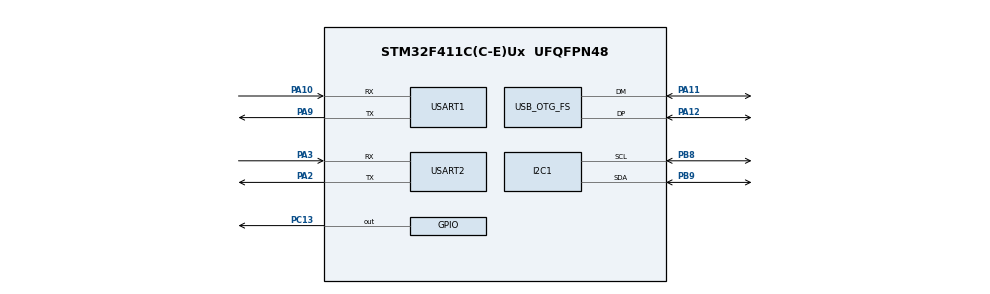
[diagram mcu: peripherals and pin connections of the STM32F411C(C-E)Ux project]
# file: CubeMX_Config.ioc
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ADC1.Channel-0\#ChannelRegularConversion=ADC_CHANNEL_TEMPSENSOR
ADC1.NbrOfConversionFlag=1
ADC1.Rank-0\#ChannelRegularConversion=1
ADC1.SamplingTime-0\#ChannelRegularConversion=ADC_SAMPLETIME_3CYCLES
ADC1.master=1
Mcu.Family=STM32F4
Mcu.Name=STM32F411C(C-E)Ux
Mcu.Package=UFQFPN48
NVIC.PriorityGroup=NVIC_PRIORITYGROUP_4
PA10.GPIO_PuPd=GPIO_PULLUP
PA10.Mode=Asynchronous
PA10.Signal=USART1_RX
PA11.Mode=Device_Only
PA11.Signal=USB_OTG_FS_DM
PA12.Mode=Device_Only
PA12.Signal=USB_OTG_FS_DP
PA13.Mode=Serial_Wire
PA13.Signal=SYS_JTMS-SWDIO
PA14.Mode=Serial_Wire
PA14.Signal=SYS_JTCK-SWCLK
PA2.Mode=Asynchronous
PA2.Signal=USART2_TX
PA3.Mode=Asynchronous
PA3.Signal=USART2_RX
PA9.GPIO_PuPd=GPIO_PULLUP
PA9.Mode=Asynchronous
PA9.Signal=USART1_TX
PB8.Mode=I2C
PB8.Signal=I2C1_SCL
PB9.Mode=I2C
PB9.Signal=I2C1_SDA
PC13-ANTI_TAMP.Signal=GPIO_Output
PC14-OSC32_IN.Mode=LSE-External-Oscillator
PC14-OSC32_IN.Signal=RCC_OSC32_IN
PC15-OSC32_OUT.Mode=LSE-External-Oscillator
PC15-OSC32_OUT.Signal=RCC_OSC32_OUT
PH0\ -\ OSC_IN.Mode=HSE-External-Oscillator
PH0\ -\ OSC_IN.Signal=RCC_OSC_IN
PH1\ -\ OSC_OUT.Mode=HSE-External-Oscillator
PH1\ -\ OSC_OUT.Signal=RCC_OSC_OUT
ProjectManager.HeapSize=0x200
ProjectManager.StackSize=0x400
ProjectManager.TargetToolchain=MDK-ARM V5
RCC.48MHZClocksFreq_Value=48000000
RCC.AHBFreq_Value=96000000
RCC.APB1CLKDivider=RCC_HCLK_DIV2
RCC.APB1Freq_Value=48000000
RCC.APB1TimFreq_Value=96000000
RCC.APB2Freq_Value=96000000
RCC.APB2TimFreq_Value=96000000
RCC.CortexFreq_Value=96000000
RCC.HCLKFreq_Value=96000000
RCC.HSE_VALUE=8000000
RCC.HSI_VALUE=16000000
RCC.PLLM=4
RCC.PLLN=96
RCC.RCC_RTC_Clock_Source=RCC_RTCCLKSOURCE_LSI
RCC.RCC_RTC_Clock_SourceVirtual=RCC_RTCCLKSOURCE_LSE
RCC.SYSCLKFreq_VALUE=96000000
RCC.SYSCLKSource=RCC_SYSCLKSOURCE_PLLCLK
RCC.VCOOutputFreq_Value=192000000
USART1.VirtualMode=VM_ASYNC
USART2.VirtualMode=VM_ASYNC
USB_OTG_FS.VirtualMode=Device_Only
VP_ADC1_TempSens_Input.Mode=IN-TempSens
VP_ADC1_Vref_Input.Mode=IN-Vrefint
VP_RTC_VS_RTC_Activate.Mode=RTC_Enabled
VP_TIM10_VS_ClockSourceINT.Mode=Enable_Timer
VP_TIM11_VS_ClockSourceINT.Mode=Enable_Timer
VP_TIM1_VS_ClockSourceINT.Mode=Internal
VP_TIM4_VS_ClockSourceINT.Mode=Internal
board=custom

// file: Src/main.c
/* USER CODE BEGIN Header */
/**
  ******************************************************************************
  * @file           : main.c
  * @brief          : Main program body
  ******************************************************************************
  * @attention
  *
  * Copyright (c) 2025 STMicroelectronics.
  * All rights reserved.
  *
  * This software is licensed under terms that can be found in the LICENSE file
  * in the root directory of this software component.
  * If no LICENSE file comes with this software, it is provided AS-IS.
  *
  ******************************************************************************
  */
/* USER CODE END Header */
#include "main.h"

 ADC_HandleTypeDef hadc1;

I2C_HandleTypeDef hi2c1;

RTC_HandleTypeDef hrtc;

TIM_HandleTypeDef htim1;
TIM_HandleTypeDef htim4;
TIM_HandleTypeDef htim10;
TIM_HandleTypeDef htim11;

UART_HandleTypeDef huart1;
UART_HandleTypeDef huart2;

PCD_HandleTypeDef hpcd_USB_OTG_FS;

void SystemClock_Config(void);
static void MX_GPIO_Init(void);
static void MX_USART1_UART_Init(void);
static void MX_RTC_Init(void);
static void MX_TIM10_Init(void);
static void MX_TIM11_Init(void);
static void MX_USB_OTG_FS_PCD_Init(void);
static void MX_ADC1_Init(void);
static void MX_TIM1_Init(void);
static void MX_TIM4_Init(void);
static void MX_USART2_UART_Init(void);
static void MX_I2C1_Init(void);

int main(void)
{

  /* MCU Configuration--------------------------------------------------------*/

  /* Reset of all peripherals, Initializes the Flash interface and the Systick. */
  HAL_Init();

  /* Configure the system clock */
  SystemClock_Config();

  /* Initialize all configured peripherals */
  MX_GPIO_Init();
  MX_USART1_UART_Init();
  MX_RTC_Init();
  MX_TIM10_Init();
  MX_TIM11_Init();
  MX_USB_OTG_FS_PCD_Init();
  MX_ADC1_Init();
  MX_TIM1_Init();
  MX_TIM4_Init();
  MX_USART2_UART_Init();
  MX_I2C1_Init();

  /* Infinite loop */
  while (1)
  {

  }
}

void SystemClock_Config(void)
{
  RCC_OscInitTypeDef RCC_OscInitStruct = {0};
  RCC_ClkInitTypeDef RCC_ClkInitStruct = {0};

  /** Configure the main internal regulator output voltage
  */
  __HAL_RCC_PWR_CLK_ENABLE();
  __HAL_PWR_VOLTAGESCALING_CONFIG(PWR_REGULATOR_VOLTAGE_SCALE1);

  /** Initializes the RCC Oscillators according to the specified parameters
  * in the RCC_OscInitTypeDef structure.
  */
  RCC_OscInitStruct.OscillatorType = RCC_OSCILLATORTYPE_HSE|RCC_OSCILLATORTYPE_LSE;
  RCC_OscInitStruct.HSEState = RCC_HSE_ON;
  RCC_OscInitStruct.LSEState = RCC_LSE_ON;
  RCC_OscInitStruct.PLL.PLLState = RCC_PLL_ON;
  RCC_OscInitStruct.PLL.PLLSource = RCC_PLLSOURCE_HSE;
  RCC_OscInitStruct.PLL.PLLM = 15;
  RCC_OscInitStruct.PLL.PLLN = 144;
  RCC_OscInitStruct.PLL.PLLP = RCC_PLLP_DIV4;
  RCC_OscInitStruct.PLL.PLLQ = 5;
  if (HAL_RCC_OscConfig(&RCC_OscInitStruct) != HAL_OK)
  {
    Error_Handler();
  }

  /** Initializes the CPU, AHB and APB buses clocks
  */
  RCC_ClkInitStruct.ClockType = RCC_CLOCKTYPE_HCLK|RCC_CLOCKTYPE_SYSCLK
                              |RCC_CLOCKTYPE_PCLK1|RCC_CLOCKTYPE_PCLK2;
  RCC_ClkInitStruct.SYSCLKSource = RCC_SYSCLKSOURCE_PLLCLK;
  RCC_ClkInitStruct.AHBCLKDivider = RCC_SYSCLK_DIV1;
  RCC_ClkInitStruct.APB1CLKDivider = RCC_HCLK_DIV2;
  RCC_ClkInitStruct.APB2CLKDivider = RCC_HCLK_DIV1;

  if (HAL_RCC_ClockConfig(&RCC_ClkInitStruct, FLASH_LATENCY_1) != HAL_OK)
  {
    Error_Handler();
  }
}

static void MX_ADC1_Init(void)
{

  ADC_ChannelConfTypeDef sConfig = {0};

  /** Configure the global features of the ADC (Clock, Resolution, Data Alignment and number of conversion)
  */
  hadc1.Instance = ADC1;
  hadc1.Init.ClockPrescaler = ADC_CLOCK_SYNC_PCLK_DIV2;
  hadc1.Init.Resolution = ADC_RESOLUTION_12B;
  hadc1.Init.ScanConvMode = DISABLE;
  hadc1.Init.ContinuousConvMode = DISABLE;
  hadc1.Init.DiscontinuousConvMode = DISABLE;
  hadc1.Init.ExternalTrigConvEdge = ADC_EXTERNALTRIGCONVEDGE_NONE;
  hadc1.Init.ExternalTrigConv = ADC_SOFTWARE_START;
  hadc1.Init.DataAlign = ADC_DATAALIGN_RIGHT;
  hadc1.Init.NbrOfConversion = 1;
  hadc1.Init.DMAContinuousRequests = DISABLE;
  hadc1.Init.EOCSelection = ADC_EOC_SINGLE_CONV;
  if (HAL_ADC_Init(&hadc1) != HAL_OK)
  {
    Error_Handler();
  }

  /** Configure for the selected ADC regular channel its corresponding rank in the sequencer and its sample time.
  */
  sConfig.Channel = ADC_CHANNEL_TEMPSENSOR;
  sConfig.Rank = 1;
  sConfig.SamplingTime = ADC_SAMPLETIME_3CYCLES;
  if (HAL_ADC_ConfigChannel(&hadc1, &sConfig) != HAL_OK)
  {
    Error_Handler();
  }

}

static void MX_I2C1_Init(void)
{

  hi2c1.Instance = I2C1;
  hi2c1.Init.ClockSpeed = 100000;
  hi2c1.Init.DutyCycle = I2C_DUTYCYCLE_2;
  hi2c1.Init.OwnAddress1 = 0;
  hi2c1.Init.AddressingMode = I2C_ADDRESSINGMODE_7BIT;
  hi2c1.Init.DualAddressMode = I2C_DUALADDRESS_DISABLE;
  hi2c1.Init.OwnAddress2 = 0;
  hi2c1.Init.GeneralCallMode = I2C_GENERALCALL_DISABLE;
  hi2c1.Init.NoStretchMode = I2C_NOSTRETCH_DISABLE;
  if (HAL_I2C_Init(&hi2c1) != HAL_OK)
  {
    Error_Handler();
  }

}

static void MX_RTC_Init(void)
{

  /** Initialize RTC Only
  */
  hrtc.Instance = RTC;
  hrtc.Init.HourFormat = RTC_HOURFORMAT_24;
  hrtc.Init.AsynchPrediv = 127;
  hrtc.Init.SynchPrediv = 255;
  hrtc.Init.OutPut = RTC_OUTPUT_DISABLE;
  hrtc.Init.OutPutPolarity = RTC_OUTPUT_POLARITY_HIGH;
  hrtc.Init.OutPutType = RTC_OUTPUT_TYPE_OPENDRAIN;
  if (HAL_RTC_Init(&hrtc) != HAL_OK)
  {
    Error_Handler();
  }

}

static void MX_TIM1_Init(void)
{

  TIM_ClockConfigTypeDef sClockSourceConfig = {0};
  TIM_MasterConfigTypeDef sMasterConfig = {0};

  htim1.Instance = TIM1;
  htim1.Init.Prescaler = 0;
  htim1.Init.CounterMode = TIM_COUNTERMODE_UP;
  htim1.Init.Period = 65535;
  htim1.Init.ClockDivision = TIM_CLOCKDIVISION_DIV1;
  htim1.Init.RepetitionCounter = 0;
  htim1.Init.AutoReloadPreload = TIM_AUTORELOAD_PRELOAD_DISABLE;
  if (HAL_TIM_Base_Init(&htim1) != HAL_OK)
  {
    Error_Handler();
  }
  sClockSourceConfig.ClockSource = TIM_CLOCKSOURCE_INTERNAL;
  if (HAL_TIM_ConfigClockSource(&htim1, &sClockSourceConfig) != HAL_OK)
  {
    Error_Handler();
  }
  sMasterConfig.MasterOutputTrigger = TIM_TRGO_RESET;
  sMasterConfig.MasterSlaveMode = TIM_MASTERSLAVEMODE_DISABLE;
  if (HAL_TIMEx_MasterConfigSynchronization(&htim1, &sMasterConfig) != HAL_OK)
  {
    Error_Handler();
  }

}

static void MX_TIM4_Init(void)
{

  TIM_ClockConfigTypeDef sClockSourceConfig = {0};
  TIM_MasterConfigTypeDef sMasterConfig = {0};

  htim4.Instance = TIM4;
  htim4.Init.Prescaler = 0;
  htim4.Init.CounterMode = TIM_COUNTERMODE_UP;
  htim4.Init.Period = 65535;
  htim4.Init.ClockDivision = TIM_CLOCKDIVISION_DIV1;
  htim4.Init.AutoReloadPreload = TIM_AUTORELOAD_PRELOAD_DISABLE;
  if (HAL_TIM_Base_Init(&htim4) != HAL_OK)
  {
    Error_Handler();
  }
  sClockSourceConfig.ClockSource = TIM_CLOCKSOURCE_INTERNAL;
  if (HAL_TIM_ConfigClockSource(&htim4, &sClockSourceConfig) != HAL_OK)
  {
    Error_Handler();
  }
  sMasterConfig.MasterOutputTrigger = TIM_TRGO_RESET;
  sMasterConfig.MasterSlaveMode = TIM_MASTERSLAVEMODE_DISABLE;
  if (HAL_TIMEx_MasterConfigSynchronization(&htim4, &sMasterConfig) != HAL_OK)
  {
    Error_Handler();
  }

}

static void MX_TIM10_Init(void)
{

  htim10.Instance = TIM10;
  htim10.Init.Prescaler = 0;
  htim10.Init.CounterMode = TIM_COUNTERMODE_UP;
  htim10.Init.Period = 65535;
  htim10.Init.ClockDivision = TIM_CLOCKDIVISION_DIV1;
  htim10.Init.AutoReloadPreload = TIM_AUTORELOAD_PRELOAD_DISABLE;
  if (HAL_TIM_Base_Init(&htim10) != HAL_OK)
  {
    Error_Handler();
  }

}

static void MX_TIM11_Init(void)
{

  htim11.Instance = TIM11;
  htim11.Init.Prescaler = 0;
  htim11.Init.CounterMode = TIM_COUNTERMODE_UP;
  htim11.Init.Period = 65535;
  htim11.Init.ClockDivision = TIM_CLOCKDIVISION_DIV1;
  htim11.Init.AutoReloadPreload = TIM_AUTORELOAD_PRELOAD_DISABLE;
  if (HAL_TIM_Base_Init(&htim11) != HAL_OK)
  {
    Error_Handler();
  }

}

static void MX_USART1_UART_Init(void)
{

  huart1.Instance = USART1;
  huart1.Init.BaudRate = 115200;
  huart1.Init.WordLength = UART_WORDLENGTH_8B;
  huart1.Init.StopBits = UART_STOPBITS_1;
  huart1.Init.Parity = UART_PARITY_NONE;
  huart1.Init.Mode = UART_MODE_TX_RX;
  huart1.Init.HwFlowCtl = UART_HWCONTROL_NONE;
  huart1.Init.OverSampling = UART_OVERSAMPLING_16;
  if (HAL_UART_Init(&huart1) != HAL_OK)
  {
    Error_Handler();
  }

}

static void MX_USART2_UART_Init(void)
{

  huart2.Instance = USART2;
  huart2.Init.BaudRate = 115200;
  huart2.Init.WordLength = UART_WORDLENGTH_8B;
  huart2.Init.StopBits = UART_STOPBITS_1;
  huart2.Init.Parity = UART_PARITY_NONE;
  huart2.Init.Mode = UART_MODE_TX_RX;
  huart2.Init.HwFlowCtl = UART_HWCONTROL_NONE;
  huart2.Init.OverSampling = UART_OVERSAMPLING_16;
  if (HAL_UART_Init(&huart2) != HAL_OK)
  {
    Error_Handler();
  }

}

static void MX_USB_OTG_FS_PCD_Init(void)
{

  hpcd_USB_OTG_FS.Instance = USB_OTG_FS;
  hpcd_USB_OTG_FS.Init.dev_endpoints = 4;
  hpcd_USB_OTG_FS.Init.speed = PCD_SPEED_FULL;
  hpcd_USB_OTG_FS.Init.dma_enable = DISABLE;
  hpcd_USB_OTG_FS.Init.phy_itface = PCD_PHY_EMBEDDED;
  hpcd_USB_OTG_FS.Init.Sof_enable = DISABLE;
  hpcd_USB_OTG_FS.Init.low_power_enable = DISABLE;
  hpcd_USB_OTG_FS.Init.lpm_enable = DISABLE;
  hpcd_USB_OTG_FS.Init.vbus_sensing_enable = DISABLE;
  hpcd_USB_OTG_FS.Init.use_dedicated_ep1 = DISABLE;
  if (HAL_PCD_Init(&hpcd_USB_OTG_FS) != HAL_OK)
  {
    Error_Handler();
  }

}

static void MX_GPIO_Init(void)
{
  GPIO_InitTypeDef GPIO_InitStruct = {0};

  /* GPIO Ports Clock Enable */
  __HAL_RCC_GPIOC_CLK_ENABLE();
  __HAL_RCC_GPIOH_CLK_ENABLE();
  __HAL_RCC_GPIOA_CLK_ENABLE();
  __HAL_RCC_GPIOB_CLK_ENABLE();

  /*Configure GPIO pin Output Level */
  HAL_GPIO_WritePin(GPIOC, GPIO_PIN_13, GPIO_PIN_RESET);

  /*Configure GPIO pin : PC13 */
  GPIO_InitStruct.Pin = GPIO_PIN_13;
  GPIO_InitStruct.Mode = GPIO_MODE_OUTPUT_PP;
  GPIO_InitStruct.Pull = GPIO_NOPULL;
  GPIO_InitStruct.Speed = GPIO_SPEED_FREQ_LOW;
  HAL_GPIO_Init(GPIOC, &GPIO_InitStruct);

}

void Error_Handler(void)
{
  __disable_irq();
  while (1)
  {
  }
}
